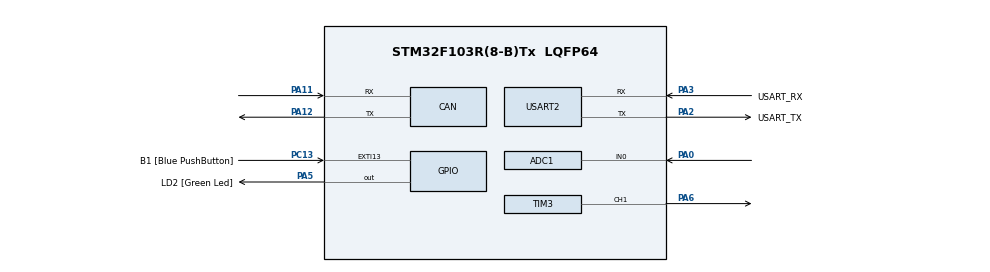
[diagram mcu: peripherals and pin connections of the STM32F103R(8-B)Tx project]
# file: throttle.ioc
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ADC1.Channel-3\#ChannelRegularConversion=ADC_CHANNEL_0
ADC1.NbrOfConversionFlag=1
ADC1.Rank-3\#ChannelRegularConversion=1
ADC1.SamplingTime-3\#ChannelRegularConversion=ADC_SAMPLETIME_1CYCLE_5
ADC1.master=1
CAN.CalculateTimeBit=12000
CAN.CalculateTimeQuantum=4000.0
Mcu.Family=STM32F1
Mcu.Name=STM32F103R(8-B)Tx
Mcu.Package=LQFP64
NVIC.EXTI15_10_IRQn=true\:0\:0\:false\:false\:true\:true\:true
NVIC.PriorityGroup=NVIC_PRIORITYGROUP_4
PA0-WKUP.Signal=ADCx_IN0
PA11.Mode=Master
PA11.Signal=CAN_RX
PA12.Mode=Master
PA12.Signal=CAN_TX
PA13.GPIO_Label=TMS
PA13.Mode=Serial_Wire
PA13.Signal=SYS_JTMS-SWDIO
PA14.GPIO_Label=TCK
PA14.Mode=Serial_Wire
PA14.Signal=SYS_JTCK-SWCLK
PA2.GPIO_Label=USART_TX
PA2.GPIO_Mode=GPIO_MODE_AF_PP
PA2.GPIO_PuPd=GPIO_NOPULL
PA2.GPIO_Speed=GPIO_SPEED_FREQ_LOW
PA2.Mode=Asynchronous
PA2.Signal=USART2_TX
PA3.GPIO_Label=USART_RX
PA3.GPIO_Mode=GPIO_MODE_AF_PP
PA3.GPIO_PuPd=GPIO_NOPULL
PA3.GPIO_Speed=GPIO_SPEED_FREQ_LOW
PA3.Mode=Asynchronous
PA3.Signal=USART2_RX
PA5.GPIO_Label=LD2 [Green Led]
PA5.GPIO_ModeDefaultOutputPP=GPIO_MODE_OUTPUT_PP
PA5.GPIO_PuPd=GPIO_NOPULL
PA5.GPIO_Speed=GPIO_SPEED_FREQ_LOW
PA5.Signal=GPIO_Output
PA6.Signal=S_TIM3_CH1
PB3.GPIO_Label=SWO
PB3.Signal=SYS_JTDO-TRACESWO
PC13-TAMPER-RTC.GPIO_Label=B1 [Blue PushButton]
PC13-TAMPER-RTC.GPIO_PuPd=GPIO_NOPULL
PC13-TAMPER-RTC.Signal=GPXTI13
PC14-OSC32_IN.Mode=LSE-External-Oscillator
PC14-OSC32_IN.Signal=RCC_OSC32_IN
PC15-OSC32_OUT.Mode=LSE-External-Oscillator
PC15-OSC32_OUT.Signal=RCC_OSC32_OUT
PD0-OSC_IN.Mode=HSE-External-Clock-Source
PD0-OSC_IN.Signal=RCC_OSC_IN
PD1-OSC_OUT.Mode=HSE-External-Clock-Source
PD1-OSC_OUT.Signal=RCC_OSC_OUT
ProjectManager.HeapSize=0x200
ProjectManager.StackSize=0x400
ProjectManager.TargetToolchain=SW4STM32
RCC.AHBFreq_Value=8000000
RCC.APB1CLKDivider=RCC_HCLK_DIV2
RCC.APB1Freq_Value=4000000
RCC.APB1TimFreq_Value=8000000
RCC.APB2Freq_Value=8000000
RCC.APB2TimFreq_Value=8000000
RCC.HCLKFreq_Value=8000000
RCC.RTCClockSelection=RCC_RTCCLKSOURCE_LSE
RCC.SYSCLKFreq_VALUE=8000000
RCC.SYSCLKSource=RCC_SYSCLKSOURCE_PLLCLK
RCC.USBFreq_Value=8000000
SH.ADCx_IN0.0=ADC1_IN0,IN0
SH.S_TIM3_CH1.0=TIM3_CH1,PWM Generation1 CH1
TIM3.Channel-PWM\ Generation1\ CH1=TIM_CHANNEL_1
USART2.VirtualMode=VM_ASYNC
VP_IWDG_VS_IWDG.Mode=IWDG_Activate
VP_TIM2_VS_ClockSourceINT.Mode=Internal
board=NUCLEO-F103RB

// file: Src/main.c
/* USER CODE BEGIN Header */
/**
 ******************************************************************************
 * @file           : main.c
 * @brief          : Main program body
 ******************************************************************************
 * @attention
 *
 * <h2><center>&copy; Copyright (c) 2019 STMicroelectronics.
 * All rights reserved.</center></h2>
 *
 * This software component is licensed by ST under BSD 3-Clause license,
 * the "License"; You may not use this file except in compliance with the
 * License. You may obtain a copy of the License at:
 *                        opensource.org/licenses/BSD-3-Clause
 *
 ******************************************************************************
 */
/* USER CODE END Header */

#include "main.h"
#include "stm32f1xx_hal.h"
#include "string.h"
#include "stdio.h"

CAN_HandleTypeDef hcan;
ADC_HandleTypeDef hadc1;
TIM_HandleTypeDef htim2;
TIM_HandleTypeDef htim3;

UART_HandleTypeDef huart2;
uint8_t req_counter = 0;
uint8_t led_no = 0;

void SystemClock_Config(void);
static void MX_GPIO_Init(void);
static void MX_CAN_Init(void);
static void MX_ADC1_Init(void);
static void MX_TIM2_Init(void);
static void MX_TIM3_Init(void);
static void MX_USART2_UART_Init(void);
void CAN_Filter_Config(void);
void CAN1_Tx(void);

//void Send_response(uint32_t StdId);
//void LED_Manage_Output(uint8_t led_no);
CAN_RxHeaderTypeDef RxHeader;
CAN_TxHeaderTypeDef TxHeader;

int main(void)
{

	/* MCU Configuration--------------------------------------------------------*/

	/* Reset of all peripherals, Initializes the Flash interface and the Systick. */
	HAL_Init();

	/* Configure the system clock */
	SystemClock_Config();

	/* Initialize all configured peripherals */
	MX_GPIO_Init();
	MX_ADC1_Init();
	MX_CAN_Init();
	MX_TIM2_Init();
	MX_TIM3_Init();
	MX_USART2_UART_Init();
	CAN_Filter_Config();
	HAL_GPIO_WritePin(GPIOC, GPIO_PIN_0, GPIO_PIN_RESET);
	HAL_GPIO_WritePin(GPIOC, GPIO_PIN_1, GPIO_PIN_RESET);
	HAL_GPIO_WritePin(GPIOC, GPIO_PIN_2, GPIO_PIN_RESET);
	HAL_GPIO_WritePin(GPIOC, GPIO_PIN_3, GPIO_PIN_RESET);

	char msg[50];
	sprintf(msg,"Init Success\r\n");
	HAL_UART_Transmit(&huart2,(uint8_t*)msg,strlen(msg),HAL_MAX_DELAY);

	if(HAL_CAN_ActivateNotification(&hcan,CAN_IT_TX_MAILBOX_EMPTY|CAN_IT_RX_FIFO0_MSG_PENDING|CAN_IT_BUSOFF)!= HAL_OK)
	{
		Error_Handler();
	}

	if( HAL_CAN_Start(&hcan) != HAL_OK)
	{
		Error_Handler();
	}

	/* Infinite loop */
	/* USER CODE BEGIN WHILE */
	//
	//	uint32_t adcval=0;
	//	int value=0;
	//
	while (1)
	{

				HAL_TIM_PWM_Stop(&htim3,TIM_CHANNEL_1);
				HAL_GPIO_WritePin(GPIOA,GPIO_PIN_7,GPIO_PIN_RESET);
				HAL_TIM_PWM_Start(&htim3,TIM_CHANNEL_1);
				sprintf(msg,"Actuating Brake\r\n");
				HAL_UART_Transmit(&huart2,(uint8_t*)msg,strlen(msg),HAL_MAX_DELAY);
                HAL_Delay(5000);
				HAL_TIM_PWM_Stop(&htim3,TIM_CHANNEL_1);
				HAL_GPIO_WritePin(GPIOA,GPIO_PIN_7,GPIO_PIN_SET);
				HAL_TIM_PWM_Start(&htim3,TIM_CHANNEL_1);
				sprintf(msg,"Releasing Brake\r\n");
				HAL_UART_Transmit(&huart2,(uint8_t*)msg,strlen(msg),HAL_MAX_DELAY);

		//		/* USER CODE END WHILE */
		//
		//		HAL_ADC_Start(&hadc1);
		//		if(HAL_ADC_PollForConversion(&hadc1,5)== HAL_OK)
		//		{
		//			adcval=HAL_ADC_GetValue(&hadc1);
		//			value=(int)adcval;
		//		}
		//		sprintf(msg,"%d\r\n",value);
		//		HAL_UART_Transmit(&huart2,(uint8_t*)msg,strlen(msg),HAL_MAX_DELAY);
		//		HAL_ADC_Stop(&hadc1);
		//		if(value>1600 && value<1900)
		//		{
		//			HAL_TIM_PWM_Stop(&htim3,TIM_CHANNEL_1);
		//			HAL_GPIO_WritePin(GPIOA,GPIO_PIN_7,GPIO_PIN_SET);
		//			if(HAL_TIM_PWM_Start(&htim3,TIM_CHANNEL_1)!=HAL_OK)
		//			{
		//				Error_Handler();
		//			}
		//			else
		//			{
		//				sprintf(msg,"%s\r\n","PWM Forward");
		//				HAL_UART_Transmit(&huart2,(uint8_t*)msg,strlen(msg),HAL_MAX_DELAY);
		//			}
		//
		//		}
		//		else if(value>1900 && value<2200)
		//		{
		//			HAL_TIM_PWM_Stop(&htim3,TIM_CHANNEL_1);
		//			HAL_GPIO_WritePin(GPIOA,GPIO_PIN_7,GPIO_PIN_RESET);
		//			if(HAL_TIM_PWM_Start(&htim3,TIM_CHANNEL_1)!=HAL_OK)
		//			{
		//				Error_Handler();
		//			}
		//			else
		//			{
		//				sprintf(msg,"%s\r\n","PWM Reverse");
		//				HAL_UART_Transmit(&huart2,(uint8_t*)msg,strlen(msg),HAL_MAX_DELAY);
		//			}
		//		}
		//		else
		//		{
		//			HAL_TIM_PWM_Stop(&htim3,TIM_CHANNEL_1);
		//			HAL_GPIO_WritePin(GPIOA,GPIO_PIN_7,GPIO_PIN_RESET);
		//		}
	}

}

void SystemClock_Config(void)
{
	RCC_OscInitTypeDef RCC_OscInitStruct = {0};
	RCC_ClkInitTypeDef RCC_ClkInitStruct = {0};

	/** Initializes the CPU, AHB and APB busses clocks
	 */
	RCC_OscInitStruct.OscillatorType = RCC_OSCILLATORTYPE_HSE;
	RCC_OscInitStruct.HSEState = RCC_HSE_BYPASS;
	RCC_OscInitStruct.HSEPredivValue = RCC_HSE_PREDIV_DIV1;
	RCC_OscInitStruct.HSIState = RCC_HSI_ON;
	RCC_OscInitStruct.PLL.PLLState = RCC_PLL_ON;
	RCC_OscInitStruct.PLL.PLLSource = RCC_PLLSOURCE_HSE;
	RCC_OscInitStruct.PLL.PLLMUL = RCC_PLL_MUL9;
	if (HAL_RCC_OscConfig(&RCC_OscInitStruct) != HAL_OK)
	{
		Error_Handler();
	}
	/** Initializes the CPU, AHB and APB busses clocks
	 */
	RCC_ClkInitStruct.ClockType = RCC_CLOCKTYPE_HCLK|RCC_CLOCKTYPE_SYSCLK
			|RCC_CLOCKTYPE_PCLK1|RCC_CLOCKTYPE_PCLK2;
	RCC_ClkInitStruct.SYSCLKSource = RCC_SYSCLKSOURCE_PLLCLK;
	RCC_ClkInitStruct.AHBCLKDivider = RCC_SYSCLK_DIV1;
	RCC_ClkInitStruct.APB1CLKDivider = RCC_HCLK_DIV2;
	RCC_ClkInitStruct.APB2CLKDivider = RCC_HCLK_DIV1;

	if (HAL_RCC_ClockConfig(&RCC_ClkInitStruct, FLASH_LATENCY_2) != HAL_OK)
	{
		Error_Handler();
	}

}

static void MX_ADC1_Init(void)
{

	ADC_ChannelConfTypeDef sConfig = {0};

	/** Common config
	 */
	hadc1.Instance = ADC1;
	hadc1.Init.ScanConvMode = ADC_SCAN_DISABLE;
	hadc1.Init.ContinuousConvMode = DISABLE;
	hadc1.Init.DiscontinuousConvMode = DISABLE;
	hadc1.Init.ExternalTrigConv = ADC_SOFTWARE_START;
	hadc1.Init.DataAlign = ADC_DATAALIGN_RIGHT;
	hadc1.Init.NbrOfConversion = 1;
	if (HAL_ADC_Init(&hadc1) != HAL_OK)
	{
		Error_Handler();
	}
	/** Configure Regular Channel
	 */
	sConfig.Channel = ADC_CHANNEL_0;
	sConfig.Rank = ADC_REGULAR_RANK_1;
	sConfig.SamplingTime = ADC_SAMPLETIME_1CYCLE_5;
	if (HAL_ADC_ConfigChannel(&hadc1, &sConfig) != HAL_OK)
	{
		Error_Handler();
	}

}

static void MX_CAN_Init(void)
{

	hcan.Instance = CAN1;
	hcan.Init.Prescaler = 18;
	hcan.Init.Mode = CAN_MODE_NORMAL;
	hcan.Init.SyncJumpWidth = CAN_SJW_1TQ;
	hcan.Init.TimeSeg1 = CAN_BS1_13TQ;
	hcan.Init.TimeSeg2 = CAN_BS2_2TQ;
	hcan.Init.TimeTriggeredMode = DISABLE;
	hcan.Init.AutoBusOff = ENABLE;
	hcan.Init.AutoWakeUp = DISABLE;
	hcan.Init.AutoRetransmission = ENABLE;
	hcan.Init.ReceiveFifoLocked = DISABLE;
	hcan.Init.TransmitFifoPriority = DISABLE;
	if (HAL_CAN_Init(&hcan) != HAL_OK)
	{
		Error_Handler();
	}

}

static void MX_TIM2_Init(void)
{

	//TIM_ClockConfigTypeDef sClockSourceConfig = {0};
	//TIM_MasterConfigTypeDef sMasterConfig = {0};

	htim2.Instance = TIM2;
	htim2.Init.Prescaler =1999;
	htim2.Init.CounterMode = TIM_COUNTERMODE_UP;
	htim2.Init.Period = 3600-1;
	//htim2.Init.ClockDivision = TIM_CLOCKDIVISION_DIV1;
	//htim2.Init.AutoReloadPreload = TIM_AUTORELOAD_PRELOAD_DISABLE;
	if (HAL_TIM_Base_Init(&htim2) != HAL_OK)
	{
		Error_Handler();
	}
	//sClockSourceConfig.ClockSource = TIM_CLOCKSOURCE_INTERNAL;
	// if (HAL_TIM_ConfigClockSource(&htim2, &sClockSourceConfig) != HAL_OK)
	// {
	//  Error_Handler();
	// }
	// sMasterConfig.MasterOutputTrigger = TIM_TRGO_RESET;
	// sMasterConfig.MasterSlaveMode = TIM_MASTERSLAVEMODE_DISABLE;
	// if (HAL_TIMEx_MasterConfigSynchronization(&htim2, &sMasterConfig) != HAL_OK)
	// {
	//  Error_Handler();
	// }

}
static void MX_TIM3_Init(void)
{

	TIM_MasterConfigTypeDef sMasterConfig = {0};
	TIM_OC_InitTypeDef sConfigOC = {0};

	htim3.Instance = TIM3;
	htim3.Init.Prescaler = 4999;
	htim3.Init.CounterMode = TIM_COUNTERMODE_UP;
	htim3.Init.Period = 1000-1;
	htim3.Init.ClockDivision = TIM_CLOCKDIVISION_DIV1;
	htim3.Init.AutoReloadPreload = TIM_AUTORELOAD_PRELOAD_DISABLE;
	if (HAL_TIM_PWM_Init(&htim3) != HAL_OK)
	{
		Error_Handler();
	}
	sMasterConfig.MasterOutputTrigger = TIM_TRGO_RESET;
	sMasterConfig.MasterSlaveMode = TIM_MASTERSLAVEMODE_DISABLE;
	if (HAL_TIMEx_MasterConfigSynchronization(&htim3, &sMasterConfig) != HAL_OK)
	{
		Error_Handler();
	}
	sConfigOC.OCMode = TIM_OCMODE_PWM1;
	sConfigOC.Pulse = (htim3.Init.Period)*1;
	sConfigOC.OCPolarity = TIM_OCPOLARITY_HIGH;
	sConfigOC.OCFastMode = TIM_OCFAST_DISABLE;
	if (HAL_TIM_PWM_ConfigChannel(&htim3, &sConfigOC, TIM_CHANNEL_1) != HAL_OK)
	{
		Error_Handler();
	}
	HAL_TIM_MspPostInit(&htim3);

}

static void MX_USART2_UART_Init(void)
{

	huart2.Instance = USART2;
	huart2.Init.BaudRate = 115200;
	huart2.Init.WordLength = UART_WORDLENGTH_8B;
	huart2.Init.StopBits = UART_STOPBITS_1;
	huart2.Init.Parity = UART_PARITY_NONE;
	huart2.Init.Mode = UART_MODE_TX_RX;
	huart2.Init.HwFlowCtl = UART_HWCONTROL_NONE;
	huart2.Init.OverSampling = UART_OVERSAMPLING_16;
	if (HAL_UART_Init(&huart2) != HAL_OK)
	{
		Error_Handler();
	}

}

static void MX_GPIO_Init(void)
{
	GPIO_InitTypeDef GPIO_InitStruct = {0};

	/* GPIO Ports Clock Enable */
	__HAL_RCC_GPIOC_CLK_ENABLE();
	__HAL_RCC_GPIOD_CLK_ENABLE();
	__HAL_RCC_GPIOA_CLK_ENABLE();
	__HAL_RCC_GPIOB_CLK_ENABLE();

	/*Configure GPIO pin Output Level */
	HAL_GPIO_WritePin(LD2_GPIO_Port, LD2_Pin, GPIO_PIN_RESET);

	/*Configure GPIO pin Output Level */
	HAL_GPIO_WritePin(GPIOC, GPIO_PIN_6|GPIO_PIN_8|GPIO_PIN_9, GPIO_PIN_RESET);

	/*Configure GPIO pin : B1_Pin */
	GPIO_InitStruct.Pin = B1_Pin;
	GPIO_InitStruct.Mode = GPIO_MODE_IT_FALLING;
	GPIO_InitStruct.Pull = GPIO_NOPULL;
	HAL_GPIO_Init(B1_GPIO_Port, &GPIO_InitStruct);

	/*Configure GPIO pin : LD2_Pin */
	GPIO_InitStruct.Pin = LD2_Pin;
	GPIO_InitStruct.Mode = GPIO_MODE_OUTPUT_PP;
	GPIO_InitStruct.Pull = GPIO_NOPULL;
	//GPIO_InitStruct.Speed = GPIO_SPEED_FREQ_LOW;
	HAL_GPIO_Init(LD2_GPIO_Port, &GPIO_InitStruct);

	/*Configure GPIO pins : PC6 PC8 PC9 */
	GPIO_InitStruct.Pin = GPIO_PIN_6|GPIO_PIN_8|GPIO_PIN_9;
	GPIO_InitStruct.Mode = GPIO_MODE_OUTPUT_PP;
	GPIO_InitStruct.Pull = GPIO_NOPULL;
	// GPIO_InitStruct.Speed = GPIO_SPEED_FREQ_LOW;
	HAL_GPIO_Init(GPIOC, &GPIO_InitStruct);

	/*Configure GPIO pin : PA7_Pin */
	GPIO_InitStruct.Pin = GPIO_PIN_7;
	GPIO_InitStruct.Mode = GPIO_MODE_OUTPUT_PP;
	GPIO_InitStruct.Pull = GPIO_NOPULL;
	GPIO_InitStruct.Speed = GPIO_SPEED_FREQ_HIGH;
	HAL_GPIO_Init(GPIOA, &GPIO_InitStruct);

	/*Configure GPIO pin : PC0_Pin */
		GPIO_InitStruct.Pin = GPIO_PIN_0;
		GPIO_InitStruct.Mode = GPIO_MODE_OUTPUT_PP;
		GPIO_InitStruct.Pull = GPIO_NOPULL;
		GPIO_InitStruct.Speed = GPIO_SPEED_FREQ_LOW;
		HAL_GPIO_Init(GPIOC, &GPIO_InitStruct);

		/*Configure GPIO pin : PC1_Pin */
		GPIO_InitStruct.Pin = GPIO_PIN_1;
		GPIO_InitStruct.Mode = GPIO_MODE_OUTPUT_PP;
		GPIO_InitStruct.Pull = GPIO_NOPULL;
		GPIO_InitStruct.Speed = GPIO_SPEED_FREQ_LOW;
		HAL_GPIO_Init(GPIOC, &GPIO_InitStruct);

		/*Configure GPIO pin : PC2_Pin */
		GPIO_InitStruct.Pin = GPIO_PIN_2;
		GPIO_InitStruct.Mode = GPIO_MODE_OUTPUT_PP;
		GPIO_InitStruct.Pull = GPIO_NOPULL;
		GPIO_InitStruct.Speed = GPIO_SPEED_FREQ_LOW;
		HAL_GPIO_Init(GPIOC, &GPIO_InitStruct);

		/*Configure GPIO pin : PC3_Pin */
		GPIO_InitStruct.Pin = GPIO_PIN_3;
		GPIO_InitStruct.Mode = GPIO_MODE_OUTPUT_PP;
		GPIO_InitStruct.Pull = GPIO_NOPULL;
		GPIO_InitStruct.Speed = GPIO_SPEED_FREQ_LOW;
		HAL_GPIO_Init(GPIOC, &GPIO_InitStruct);

	/* EXTI interrupt init*/
	HAL_NVIC_SetPriority(EXTI15_10_IRQn, 0, 0);
	HAL_NVIC_EnableIRQ(EXTI15_10_IRQn);

}

void HAL_TIM_PeriodElapsedCallback(TIM_HandleTypeDef *htim)
{
	// CAN_TxHeaderTypeDef TxHeader;

	CAN1_Tx();

}
void CAN_Filter_Config(void)
{
	CAN_FilterTypeDef can1_filter_init;

	can1_filter_init.FilterActivation = ENABLE;
	can1_filter_init.FilterBank  = 0;
	can1_filter_init.FilterFIFOAssignment = CAN_RX_FIFO0;
	can1_filter_init.FilterIdHigh = 0x0000;
	can1_filter_init.FilterIdLow = 0x0000;
	can1_filter_init.FilterMaskIdHigh = 0x0000;
	can1_filter_init.FilterMaskIdLow = 0x0000;
	can1_filter_init.FilterMode = CAN_FILTERMODE_IDMASK;
	can1_filter_init.FilterScale = CAN_FILTERSCALE_32BIT;

	if( HAL_CAN_ConfigFilter(&hcan,&can1_filter_init) != HAL_OK)
	{
		Error_Handler();
	}

}
void HAL_CAN_TxMailbox0CompleteCallback(CAN_HandleTypeDef *hcan)
{
	char msg[100];
	sprintf(msg,"Message Transmitted:M0\r\n");
	HAL_UART_Transmit(&huart2,(uint8_t*)msg,strlen(msg),HAL_MAX_DELAY);

}

void HAL_CAN_TxMailbox1CompleteCallback(CAN_HandleTypeDef *hcan)
{
	char msg[100];
	sprintf(msg,"Message Transmitted:M1\r\n");
	HAL_UART_Transmit(&huart2,(uint8_t*)msg,strlen(msg),HAL_MAX_DELAY);

}

void HAL_CAN_TxMailbox2CompleteCallback(CAN_HandleTypeDef *hcan)
{
	char msg[100];
	sprintf(msg,"Message Transmitted:M2\r\n");
	HAL_UART_Transmit(&huart2,(uint8_t*)msg,strlen(msg),HAL_MAX_DELAY);

}

void HAL_CAN_RxFifo0MsgPendingCallback(CAN_HandleTypeDef *hcan)
{
	// CAN_RxHeaderTypeDef RxHeader;
	uint8_t rcvd_msg[8];

	char msg[100];
	int b1=0,b2=0,b3=0,b4=0,b5=0,b6=0,b7=0,b8=0;
	//while(! HAL_CAN_GetRxFifoFillLevel(&hcan,CAN_RX_FIFO0));
	if(HAL_CAN_GetRxMessage(hcan,CAN_RX_FIFO0,&RxHeader,rcvd_msg) != HAL_OK)
	{
		Error_Handler();
	}
	if (RxHeader.StdId == 0x65D && RxHeader.RTR==0)
	{
		//LED_Manage_Output(rcvd_msg[0]);
		b1=rcvd_msg[0], b2=rcvd_msg[1], b3=rcvd_msg[2], b4=rcvd_msg[3],b5=rcvd_msg[4], b6=rcvd_msg[5], b7=rcvd_msg[6],b8=rcvd_msg[7];
		sprintf(msg,"Message Received : ID-%x %d %d %d %d %d %d %d %d \r\n",RxHeader.StdId,b1,b2,b3,b4,b5,b6,b7,b8);
		HAL_UART_Transmit(&huart2,(uint8_t*)msg,strlen(msg),HAL_MAX_DELAY);
	}
	if(b8==65 && b4==1 && b5==1)
	{
	if(b2==1)
	{
		HAL_TIM_PWM_Stop(&htim3,TIM_CHANNEL_1);
		HAL_GPIO_WritePin(GPIOA,GPIO_PIN_7,GPIO_PIN_SET);
		HAL_TIM_PWM_Start(&htim3,TIM_CHANNEL_1);
		sprintf(msg,"Actuating Brake\r\n");
		HAL_UART_Transmit(&huart2,(uint8_t*)msg,strlen(msg),HAL_MAX_DELAY);
	}
	else
	{
		HAL_TIM_PWM_Stop(&htim3,TIM_CHANNEL_1);
		HAL_GPIO_WritePin(GPIOA,GPIO_PIN_7,GPIO_PIN_RESET);
		HAL_TIM_PWM_Start(&htim3,TIM_CHANNEL_1);
		sprintf(msg,"Releasing Brake\r\n");
		HAL_UART_Transmit(&huart2,(uint8_t*)msg,strlen(msg),HAL_MAX_DELAY);
	}
	}
//	if(b4==1)
//		{
//			HAL_GPIO_WritePin(GPIOC, GPIO_PIN_3, GPIO_PIN_SET);
//
//		}
//		else
//		{
//			HAL_GPIO_WritePin(GPIOC, GPIO_PIN_3, GPIO_PIN_RESET);
//		}
//		if(b5==1)
//		{
//			HAL_GPIO_WritePin(GPIOC, GPIO_PIN_1, GPIO_PIN_SET);
//
//		}
//		else
//		{
//			HAL_GPIO_WritePin(GPIOC, GPIO_PIN_1, GPIO_PIN_RESET);
//		}
//		if(b6==1)
//		{
//			HAL_GPIO_WritePin(GPIOC, GPIO_PIN_2, GPIO_PIN_SET);
//
//		}
//		else
//		{
//			HAL_GPIO_WritePin(GPIOC, GPIO_PIN_2, GPIO_PIN_RESET);
//		}
//		if(b7==1)
//		{
//			HAL_GPIO_WritePin(GPIOC, GPIO_PIN_0, GPIO_PIN_SET);
//
//		}
//		else
//		{
//			HAL_GPIO_WritePin(GPIOC, GPIO_PIN_0, GPIO_PIN_RESET);
//		}

}

void HAL_CAN_ErrorCallback(CAN_HandleTypeDef *hcan)
{

	char msg[100];
	sprintf(msg,"CAN Error Detected\r\n");
	HAL_UART_Transmit(&huart2,(uint8_t*)msg,strlen(msg),HAL_MAX_DELAY);
}
int i = 0;
void CAN1_Tx()
{
	//CAN_TxHeaderTypeDef TxHeader;

	uint32_t TxMailbox;

	//	uint8_t message;
	uint8_t a[8] = {0,100,0,0,1,0,1,'F'};;

	TxHeader.DLC = 8;
	TxHeader.StdId = 0x65D;
	TxHeader.IDE   = CAN_ID_STD;
	TxHeader.RTR = CAN_RTR_DATA;

	char msg[100];
	sprintf(msg,"Inside CAN1 Tx \r\n");
	HAL_UART_Transmit(&huart2,(uint8_t*)msg,strlen(msg),HAL_MAX_DELAY);

	//message = ++led_no;
	//	message = a[i++];
	//	if(i == 5)
	//	{
	//		i =0;
	//	}

	//if(led_no == 3)
	//{
	//    led_no = 0;
	//}

	//HAL_GPIO_WritePin(LD2_GPIO_Port, LD2_Pin, GPIO_PIN_SET);

	//int x=HAL_CA;N_AddTxMessage(&hcan,&TxHeader,&message,&TxMailbox);
	if( HAL_CAN_AddTxMessage(&hcan,&TxHeader,a,&TxMailbox) != HAL_OK)
	{
		sprintf(msg,"CAN Error.. \r\n");
		HAL_UART_Transmit(&huart2,(uint8_t*)msg,strlen(msg),HAL_MAX_DELAY);
		Error_Handler();
	}

}

void Error_Handler(void)
{
}

/************************ (C) COPYRIGHT STMicroelectronics *****END OF FILE****/
